VERSION 5.7 ;
BUSBITCHARS "[]" ;
DIVIDERCHAR "/" ;

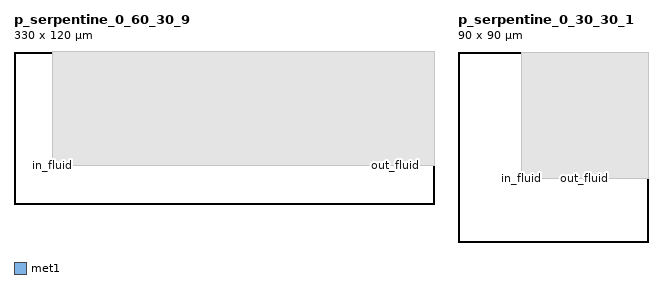
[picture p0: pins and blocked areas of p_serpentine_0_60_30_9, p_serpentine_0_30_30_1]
MACRO p_serpentine_0_60_30_9
  CLASS CORE ;
  ORIGIN  0 0 ;
  FOREIGN p_serpentine_0_60_30_9 0 0 ;
  SIZE 330 BY 120 ;
  SYMMETRY X Y ;
  SITE CoreSite ;
  PIN in_fluid
    DIRECTION INPUT ;
    USE SIGNAL ;
    PORT
      LAYER met1 ;
        RECT 29.5 29.5 30.5 30.5 ;
    END
  END in_fluid
  PIN out_fluid
    DIRECTION OUTPUT ;
    USE SIGNAL ;
    PORT
      LAYER met1 ;
        RECT 299.5 29.5 300.5 30.5 ;
    END
  END out_fluid
  OBS
    LAYER met1 ;
      RECT 30 30 330 120 ;
  END
  PROPERTY CatenaDesignType "deviceLevel" ;
END p_serpentine_0_60_30_9

MACRO p_serpentine_0_30_30_1
  CLASS CORE ;
  ORIGIN  0 0 ;
  FOREIGN p_serpentine_0_30_30_1 0 0 ;
  SIZE 90 BY 90 ;
  SYMMETRY X Y ;
  SITE CoreSite ;
  PIN in_fluid
    DIRECTION INPUT ;
    USE SIGNAL ;
    PORT
      LAYER met1 ;
        RECT 29.5 29.5 30.5 30.5 ;
    END
  END in_fluid
  PIN out_fluid
    DIRECTION OUTPUT ;
    USE SIGNAL ;
    PORT
      LAYER met1 ;
        RECT 59.5 29.5 60.5 30.5 ;
    END
  END out_fluid
  OBS
    LAYER met1 ;
      RECT 30 30 90 90 ;
  END
  PROPERTY CatenaDesignType "deviceLevel" ;
END p_serpentine_0_30_30_1

